VERSION 5.8 ;
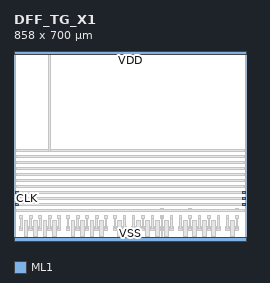
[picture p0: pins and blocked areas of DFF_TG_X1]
MACRO DFF_TG_X1
  CLASS CORE ;
  ORIGIN 0 0 ;
  SIZE 858 BY 700 ;
  SITE ICPS2023_5_ROW700 ;
  PIN D
    DIRECTION INPUT ;
    USE SIGNAL ;
    PORT
      LAYER ML1 ;
        RECT 5 130 15 140 ;
        RECT 843 130 853 140 ;
    END
  END D
  PIN CLK
    DIRECTION INPUT ;
    USE SIGNAL ;
    PORT
      LAYER ML1 ;
        RECT 5 152 15 162 ;
        RECT 843 152 853 162 ;
    END
  END CLK
  PIN Q
    DIRECTION OUTPUT ;
    USE SIGNAL ;
    PORT
      LAYER ML1 ;
        RECT 5 174 15 184 ;
        RECT 843 174 853 184 ;
    END
  END Q
  PIN VDD
    DIRECTION INOUT ;
    USE POWER ;
    PORT
      LAYER ML1 ;
        RECT 0 688 858 700 ;
    END
  END VDD
  PIN VSS
    DIRECTION INOUT ;
    USE GROUND ;
    PORT
      LAYER ML1 ;
        RECT 0 0 858 12 ;
    END
  END VSS
  OBS
    LAYER ML1 ;
      RECT 20 39.5 33 52.5 ;
      RECT 55 39.5 68 52.5 ;
      RECT 90 39.5 103 52.5 ;
      RECT 125 39.5 138 52.5 ;
      RECT 160 39.5 173 52.5 ;
      RECT 37.5 16 50.5 29 ;
      RECT 37.5 63 50.5 76 ;
      RECT 37 16 51 76 ;
      RECT 72.5 16 85.5 29 ;
      RECT 72.5 63 85.5 76 ;
      RECT 72 16 86 76 ;
      RECT 107.5 16 120.5 29 ;
      RECT 107.5 63 120.5 76 ;
      RECT 107 16 121 76 ;
      RECT 142.5 16 155.5 29 ;
      RECT 142.5 63 155.5 76 ;
      RECT 142 16 156 76 ;
      RECT 23.5 46 29.5 89 ;
      RECT 21.5 84 31.5 94 ;
      RECT 21.5 130 31.5 140 ;
      RECT 58.5 46 64.5 89 ;
      RECT 56.5 84 66.5 94 ;
      RECT 56.5 196 66.5 206 ;
      RECT 93.5 46 99.5 89 ;
      RECT 91.5 84 101.5 94 ;
      RECT 91.5 218 101.5 228 ;
      RECT 128.5 46 134.5 89 ;
      RECT 126.5 84 136.5 94 ;
      RECT 126.5 328 136.5 338 ;
      RECT 163.5 46 169.5 89 ;
      RECT 161.5 84 171.5 94 ;
      RECT 161.5 262 171.5 272 ;
      RECT 39 152 49 162 ;
      RECT 74 262 84 272 ;
      RECT 109 240 119 250 ;
      RECT 144 152 154 162 ;
      RECT 193 39.5 206 52.5 ;
      RECT 228 39.5 241 52.5 ;
      RECT 263 39.5 276 52.5 ;
      RECT 298 39.5 311 52.5 ;
      RECT 333 39.5 346 52.5 ;
      RECT 210.5 16 223.5 29 ;
      RECT 210.5 63 223.5 76 ;
      RECT 210 16 224 76 ;
      RECT 245.5 16 258.5 29 ;
      RECT 245.5 63 258.5 76 ;
      RECT 245 16 259 76 ;
      RECT 280.5 16 293.5 29 ;
      RECT 280.5 63 293.5 76 ;
      RECT 280 16 294 76 ;
      RECT 315.5 16 328.5 29 ;
      RECT 315.5 63 328.5 76 ;
      RECT 315 16 329 76 ;
      RECT 196.5 46 202.5 89 ;
      RECT 194.5 84 204.5 94 ;
      RECT 194.5 240 204.5 250 ;
      RECT 231.5 46 237.5 89 ;
      RECT 229.5 84 239.5 94 ;
      RECT 229.5 328 239.5 338 ;
      RECT 266.5 46 272.5 89 ;
      RECT 264.5 84 274.5 94 ;
      RECT 264.5 174 274.5 184 ;
      RECT 301.5 46 307.5 89 ;
      RECT 299.5 84 309.5 94 ;
      RECT 299.5 306 309.5 316 ;
      RECT 336.5 46 342.5 89 ;
      RECT 334.5 84 344.5 94 ;
      RECT 334.5 218 344.5 228 ;
      RECT 212 196 222 206 ;
      RECT 247 284 257 294 ;
      RECT 282 152 292 162 ;
      RECT 317 262 327 272 ;
      RECT 366 39.5 379 52.5 ;
      RECT 401 39.5 414 52.5 ;
      RECT 383.5 16 396.5 29 ;
      RECT 383.5 63 396.5 76 ;
      RECT 383 16 397 76 ;
      RECT 369.5 46 375.5 89 ;
      RECT 367.5 84 377.5 94 ;
      RECT 367.5 284 377.5 294 ;
      RECT 404.5 46 410.5 89 ;
      RECT 402.5 84 412.5 94 ;
      RECT 402.5 328 412.5 338 ;
      RECT 385 306 395 316 ;
      RECT 434 39.5 447 52.5 ;
      RECT 469 39.5 482 52.5 ;
      RECT 504 39.5 517 52.5 ;
      RECT 539 39.5 552 52.5 ;
      RECT 574 39.5 587 52.5 ;
      RECT 451.5 16 464.5 29 ;
      RECT 451.5 63 464.5 76 ;
      RECT 451 16 465 76 ;
      RECT 486.5 16 499.5 29 ;
      RECT 486.5 63 499.5 76 ;
      RECT 486 16 500 76 ;
      RECT 521.5 16 534.5 29 ;
      RECT 521.5 63 534.5 76 ;
      RECT 521 16 535 76 ;
      RECT 556.5 16 569.5 29 ;
      RECT 556.5 63 569.5 76 ;
      RECT 556 16 570 76 ;
      RECT 437.5 46 443.5 89 ;
      RECT 435.5 84 445.5 94 ;
      RECT 435.5 130 445.5 140 ;
      RECT 472.5 46 478.5 89 ;
      RECT 470.5 84 480.5 94 ;
      RECT 470.5 196 480.5 206 ;
      RECT 507.5 46 513.5 89 ;
      RECT 505.5 84 515.5 94 ;
      RECT 505.5 218 515.5 228 ;
      RECT 542.5 46 548.5 89 ;
      RECT 540.5 84 550.5 94 ;
      RECT 540.5 108 550.5 118 ;
      RECT 577.5 46 583.5 89 ;
      RECT 575.5 84 585.5 94 ;
      RECT 575.5 262 585.5 272 ;
      RECT 453 262 463 272 ;
      RECT 488 152 498 162 ;
      RECT 523 240 533 250 ;
      RECT 558 152 568 162 ;
      RECT 607 39.5 620 52.5 ;
      RECT 642 39.5 655 52.5 ;
      RECT 677 39.5 690 52.5 ;
      RECT 712 39.5 725 52.5 ;
      RECT 747 39.5 760 52.5 ;
      RECT 624.5 16 637.5 29 ;
      RECT 624.5 63 637.5 76 ;
      RECT 624 16 638 76 ;
      RECT 659.5 16 672.5 29 ;
      RECT 659.5 63 672.5 76 ;
      RECT 659 16 673 76 ;
      RECT 694.5 16 707.5 29 ;
      RECT 694.5 63 707.5 76 ;
      RECT 694 16 708 76 ;
      RECT 729.5 16 742.5 29 ;
      RECT 729.5 63 742.5 76 ;
      RECT 729 16 743 76 ;
      RECT 610.5 46 616.5 89 ;
      RECT 608.5 84 618.5 94 ;
      RECT 608.5 240 618.5 250 ;
      RECT 645.5 46 651.5 89 ;
      RECT 643.5 84 653.5 94 ;
      RECT 643.5 108 653.5 118 ;
      RECT 680.5 46 686.5 89 ;
      RECT 678.5 84 688.5 94 ;
      RECT 678.5 174 688.5 184 ;
      RECT 715.5 46 721.5 89 ;
      RECT 713.5 84 723.5 94 ;
      RECT 713.5 306 723.5 316 ;
      RECT 750.5 46 756.5 89 ;
      RECT 748.5 84 758.5 94 ;
      RECT 748.5 218 758.5 228 ;
      RECT 626 196 636 206 ;
      RECT 661 284 671 294 ;
      RECT 696 262 706 272 ;
      RECT 731 152 741 162 ;
      RECT 780 39.5 793 52.5 ;
      RECT 815 39.5 828 52.5 ;
      RECT 797.5 16 810.5 29 ;
      RECT 797.5 63 810.5 76 ;
      RECT 797 16 811 76 ;
      RECT 783.5 46 789.5 89 ;
      RECT 781.5 84 791.5 94 ;
      RECT 781.5 284 791.5 294 ;
      RECT 818.5 46 824.5 89 ;
      RECT 816.5 84 826.5 94 ;
      RECT 816.5 108 826.5 118 ;
      RECT 799 306 809 316 ;
      RECT 10 110 848 116 ;
      RECT 10 132 848 138 ;
      RECT 10 154 848 160 ;
      RECT 10 176 848 182 ;
      RECT 10 198 848 204 ;
      RECT 10 220 848 226 ;
      RECT 10 242 848 248 ;
      RECT 10 264 848 270 ;
      RECT 10 286 848 292 ;
      RECT 10 308 848 314 ;
      RECT 10 330 848 336 ;
      RECT 542.5 3 548.5 92 ;
      RECT 128.5 330 134.5 697 ;
  END
END DFF_TG_X1
